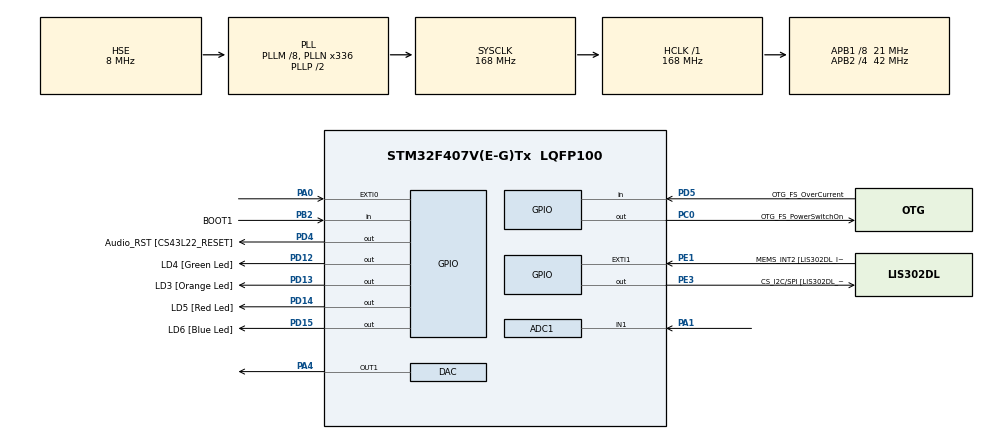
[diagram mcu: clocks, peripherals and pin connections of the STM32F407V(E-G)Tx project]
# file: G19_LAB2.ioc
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ADC1.Channel-0\#ChannelRegularConversion=ADC_CHANNEL_1
ADC1.NbrOfConversionFlag=1
ADC1.Rank-0\#ChannelRegularConversion=1
ADC1.Resolution=ADC_RESOLUTION_8B
ADC1.SamplingTime-0\#ChannelRegularConversion=ADC_SAMPLETIME_3CYCLES
ADC1.master=1
Mcu.Family=STM32F4
Mcu.Name=STM32F407V(E-G)Tx
Mcu.Package=LQFP100
NVIC.ADC_IRQn=true\:0\:0\:false\:false\:true
NVIC.EXTI0_IRQn=true\:0\:0\:false\:false\:true
NVIC.PriorityGroup=NVIC_PRIORITYGROUP_0
PA0-WKUP.Signal=GPXTI0
PA1.Signal=ADCx_IN1
PA10.GPIO_Label=OTG_FS_ID
PA10.GPIO_Mode=GPIO_MODE_AF_PP
PA10.GPIO_PuPd=GPIO_NOPULL
PA10.GPIO_Speed=GPIO_SPEED_FREQ_LOW
PA10.Signal=USB_OTG_FS_ID
PA11.GPIO_Label=OTG_FS_DM
PA11.GPIO_Mode=GPIO_MODE_AF_PP
PA11.GPIO_PuPd=GPIO_NOPULL
PA11.GPIO_Speed=GPIO_SPEED_FREQ_LOW
PA11.Signal=USB_OTG_FS_DM
PA12.GPIO_Label=OTG_FS_DP
PA12.GPIO_Mode=GPIO_MODE_AF_PP
PA12.GPIO_PuPd=GPIO_NOPULL
PA12.GPIO_Speed=GPIO_SPEED_FREQ_LOW
PA12.Signal=USB_OTG_FS_DP
PA13.GPIO_Label=SWDIO
PA13.Signal=SYS_JTMS-SWDIO
PA14.GPIO_Label=SWCLK
PA14.Signal=SYS_JTCK-SWCLK
PA4.Signal=COMP_DAC1_group
PA5.GPIO_Label=SPI1_SCK [LIS302DL_SCL/SPC]
PA5.GPIO_Mode=GPIO_MODE_AF_PP
PA5.GPIO_PuPd=GPIO_NOPULL
PA5.GPIO_Speed=GPIO_SPEED_FREQ_LOW
PA5.Signal=SPI1_SCK
PA6.GPIO_Label=SPI1_MISO [LIS302DL_SDO]
PA6.GPIO_Mode=GPIO_MODE_AF_PP
PA6.GPIO_PuPd=GPIO_NOPULL
PA6.GPIO_Speed=GPIO_SPEED_FREQ_LOW
PA6.Signal=SPI1_MISO
PA7.GPIO_Label=SPI1_MOSI [LIS302DL_SDA/SDI/SDO]
PA7.GPIO_Mode=GPIO_MODE_AF_PP
PA7.GPIO_PuPd=GPIO_NOPULL
PA7.GPIO_Speed=GPIO_SPEED_FREQ_LOW
PA7.Signal=SPI1_MOSI
PA9.GPIO_Label=VBUS_FS
PA9.GPIO_Mode=GPIO_MODE_INPUT
PA9.GPIO_PuPd=GPIO_NOPULL
PA9.Signal=USB_OTG_FS_VBUS
PB10.GPIO_Label=CLK_IN [MP45DT02_CLK]
PB10.GPIO_Mode=GPIO_MODE_AF_PP
PB10.GPIO_PuPd=GPIO_NOPULL
PB10.GPIO_Speed=GPIO_SPEED_FREQ_LOW
PB10.Signal=I2S2_CK
PB2.GPIO_Label=BOOT1
PB2.GPIO_Mode=GPIO_MODE_INPUT
PB2.GPIO_PuPd=GPIO_NOPULL
PB2.Signal=GPIO_Input
PB3.GPIO_Label=SWO
PB3.Signal=SYS_JTDO-SWO
PB6.GPIO_Label=Audio_SCL [CS43L22_SCL]
PB6.GPIO_Mode=GPIO_MODE_AF_OD
PB6.GPIO_PuPd=GPIO_NOPULL
PB6.GPIO_Speed=GPIO_SPEED_FREQ_LOW
PB6.Signal=I2C1_SCL
PB9.GPIO_Label=Audio_SDA [CS43L22_SDA]
PB9.GPIO_Mode=GPIO_MODE_AF_OD
PB9.GPIO_PuPd=GPIO_NOPULL
PB9.GPIO_Speed=GPIO_SPEED_FREQ_LOW
PB9.Signal=I2C1_SDA
PC0.GPIO_Label=OTG_FS_PowerSwitchOn
PC0.GPIO_PuPd=GPIO_NOPULL
PC0.GPIO_Speed=GPIO_SPEED_FREQ_LOW
PC0.PinState=GPIO_PIN_SET
PC0.Signal=GPIO_Output
PC10.GPIO_Label=I2S3_SCK [CS43L22_SCLK]
PC10.GPIO_Mode=GPIO_MODE_AF_PP
PC10.GPIO_PuPd=GPIO_NOPULL
PC10.GPIO_Speed=GPIO_SPEED_FREQ_LOW
PC10.Signal=I2S3_CK
PC12.GPIO_Label=I2S3_SD [CS43L22_SDIN]
PC12.GPIO_Mode=GPIO_MODE_AF_PP
PC12.GPIO_PuPd=GPIO_NOPULL
PC12.GPIO_Speed=GPIO_SPEED_FREQ_LOW
PC12.Signal=I2S3_SD
PC14-OSC32_IN.GPIO_Label=PC14-OSC32_IN
PC14-OSC32_IN.Signal=RCC_OSC32_IN
PC15-OSC32_OUT.GPIO_Label=PC15-OSC32_OUT
PC15-OSC32_OUT.Signal=RCC_OSC32_OUT
PC3.GPIO_Label=PDM_OUT [MP45DT02_DOUT]
PC3.GPIO_Mode=GPIO_MODE_AF_PP
PC3.GPIO_PuPd=GPIO_NOPULL
PC3.GPIO_Speed=GPIO_SPEED_FREQ_LOW
PC3.Signal=I2S2_SD
PC7.GPIO_Label=I2S3_MCK [CS43L22_MCLK]
PC7.GPIO_Mode=GPIO_MODE_AF_PP
PC7.GPIO_PuPd=GPIO_NOPULL
PC7.GPIO_Speed=GPIO_SPEED_FREQ_LOW
PC7.Signal=I2S3_MCK
PD12.GPIO_Label=LD4 [Green Led]
PD12.GPIO_PuPd=GPIO_NOPULL
PD12.GPIO_Speed=GPIO_SPEED_FREQ_LOW
PD12.Signal=GPIO_Output
PD13.GPIO_Label=LD3 [Orange Led]
PD13.GPIO_PuPd=GPIO_NOPULL
PD13.GPIO_Speed=GPIO_SPEED_FREQ_LOW
PD13.Signal=GPIO_Output
PD14.GPIO_Label=LD5 [Red Led]
PD14.GPIO_PuPd=GPIO_NOPULL
PD14.GPIO_Speed=GPIO_SPEED_FREQ_LOW
PD14.Signal=GPIO_Output
PD15.GPIO_Label=LD6 [Blue Led]
PD15.GPIO_PuPd=GPIO_NOPULL
PD15.GPIO_Speed=GPIO_SPEED_FREQ_LOW
PD15.Signal=GPIO_Output
PD4.GPIO_Label=Audio_RST [CS43L22_RESET]
PD4.GPIO_PuPd=GPIO_NOPULL
PD4.GPIO_Speed=GPIO_SPEED_FREQ_LOW
PD4.Signal=GPIO_Output
PD5.GPIO_Label=OTG_FS_OverCurrent
PD5.GPIO_Mode=GPIO_MODE_INPUT
PD5.GPIO_PuPd=GPIO_NOPULL
PD5.Signal=GPIO_Input
PE1.GPIO_Label=MEMS_INT2 [LIS302DL_INT2]
PE1.GPIO_ModeDefaultEXTI=GPIO_MODE_EVT_RISING
PE1.GPIO_PuPd=GPIO_NOPULL
PE1.Signal=GPXTI1
PE3.GPIO_Label=CS_I2C/SPI [LIS302DL_CS_I2C/SPI]
PE3.GPIO_PuPd=GPIO_NOPULL
PE3.GPIO_Speed=GPIO_SPEED_FREQ_LOW
PE3.Signal=GPIO_Output
PH0-OSC_IN.GPIO_Label=PH0-OSC_IN
PH0-OSC_IN.Mode=HSE-External-Oscillator
PH0-OSC_IN.Signal=RCC_OSC_IN
PH1-OSC_OUT.GPIO_Label=PH1-OSC_OUT
PH1-OSC_OUT.Mode=HSE-External-Oscillator
PH1-OSC_OUT.Signal=RCC_OSC_OUT
ProjectManager.HeapSize=0x200
ProjectManager.StackSize=0x400
ProjectManager.TargetToolchain=MDK-ARM V5
RCC.48MHZClocksFreq_Value=48000000
RCC.AHBFreq_Value=168000000
RCC.APB1CLKDivider=RCC_HCLK_DIV8
RCC.APB1Freq_Value=21000000
RCC.APB1TimFreq_Value=42000000
RCC.APB2CLKDivider=RCC_HCLK_DIV4
RCC.APB2Freq_Value=42000000
RCC.APB2TimFreq_Value=84000000
RCC.CortexFreq_Value=168000000
RCC.HCLKFreq_Value=168000000
RCC.HSE_VALUE=8000000
RCC.HSI_VALUE=16000000
RCC.LSE_VALUE=32768
RCC.PLLM=8
RCC.PLLN=336
RCC.PLLQ=7
RCC.PLLSourceVirtual=RCC_PLLSOURCE_HSE
RCC.SYSCLKFreq_VALUE=168000000
RCC.SYSCLKSource=RCC_SYSCLKSOURCE_PLLCLK
RCC.VCOOutputFreq_Value=336000000
SH.ADCx_IN1.0=ADC1_IN1,IN1
SH.COMP_DAC1_group.0=DAC_OUT1,DAC_OUT1
board=STM32F4DISCOVERY

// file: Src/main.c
/**
 ******************************************************************************
 * @file    	main.c
 * @brief       Main program body
 ******************************************************************************
 ** This notice applies to any and all portions of this file
 * that are not between comment pairs USER CODE BEGIN and
 * USER CODE END. Other portions of this file, whether
 * inserted by the user or by software development tools
 * are owned by their respective copyright owners.
 *
 * COPYRIGHT(c) 2018 STMicroelectronics
 *
 * Redistribution and use in source and binary forms, with or without modification,
 * are permitted provided that the following conditions are met:
 *   1. Redistributions of source code must retain the above copyright notice,
 *      this list of conditions and the following disclaimer.
 *   2. Redistributions in binary form must reproduce the above copyright notice,
 *      this list of conditions and the following disclaimer in the documentation
 *      and/or other materials provided with the distribution.
 *   3. Neither the name of STMicroelectronics nor the names of its contributors
 *      may be used to endorse or promote products derived from this software
 *      without specific prior written permission.
 *
 * THIS SOFTWARE IS PROVIDED BY THE COPYRIGHT HOLDERS AND CONTRIBUTORS "AS IS"
 * AND ANY EXPRESS OR IMPLIED WARRANTIES, INCLUDING, BUT NOT LIMITED TO, THE
 * IMPLIED WARRANTIES OF MERCHANTABILITY AND FITNESS FOR A PARTICULAR PURPOSE ARE
 * DISCLAIMED. IN NO EVENT SHALL THE COPYRIGHT HOLDER OR CONTRIBUTORS BE LIABLE
 * FOR ANY DIRECT, INDIRECT, INCIDENTAL, SPECIAL, EXEMPLARY, OR CONSEQUENTIAL
 * DAMAGES (INCLUDING, BUT NOT LIMITED TO, PROCUREMENT OF SUBSTITUTE GOODS OR
 * SERVICES; LOSS OF USE, DATA, OR PROFITS; OR BUSINESS INTERRUPTION) HOWEVER
 * CAUSED AND ON ANY THEORY OF LIABILITY, WHETHER IN CONTRACT, STRICT LIABILITY,
 * OR TORT (INCLUDING NEGLIGENCE OR OTHERWISE) ARISING IN ANY WAY OUT OF THE USE
 * OF THIS SOFTWARE, EVEN IF ADVISED OF THE POSSIBILITY OF SUCH DAMAGE.
 *
 ******************************************************************************
 */
#include "main.h"
#include "voltmeter.h"
#include "stm32f4xx_hal.h"

/* @brief Frequency in Hz of SysTick interrupts*/
#define SYSTICK_FREQUENCY 200
/* @brief Resolution in bits of ADC readings*/
#define ADC_RES 8

/** @brief Handle to the analog to digital converter interface*/
ADC_HandleTypeDef hadc1;
/** @brief Handle to the digital to analog converter interface*/
DAC_HandleTypeDef hdac;

void SystemClock_Config(void);
static void MX_GPIO_Init(void);
static void MX_ADC1_Init(void);
static void MX_DAC_Init(void);

/** @brief Stores latest ADC reading (digital) */
int adc_val;
/** @brief Stores latest digital value sent to the DAC */
int dac_val;
/** @brief Stores the latest values for each display mode (RMS, min, max) */
float results[3];

/** @brief Flag to change display mode, handled in EXTI0_IRQHandler() and SysTick_Handler() */
int change_mode = 0;

/** @brief Dictates which value from results[] to display */
int display_mode = RMS_MODE;

/** @brief Keeps track of SysTick interrupts for use as a software counter */
int counter = 0;

/**
 * @brief Callback function invoked when ADC has finished converting a reading
 * @param hadc Handle to the ADC unit that has finished converting a value
 * @retval None
 */
void HAL_ADC_ConvCpltCallback(ADC_HandleTypeDef* hadc) {
	adc_val = HAL_ADC_GetValue(hadc);
	float filtered_val;
	FIR_C(adc_val, &filtered_val);
	float voltage_reading = 3.3 * filtered_val / ((1 << ADC_RES) - 1.0);
	plot_point(voltage_reading, results);
}

/**
 * @brief Turns on appropriate display segments
 * @param code Byte corresponding to the segments to turn on
 * @retval None
 */
void display_num(char code) {
	if(code & SEG7_A) HAL_GPIO_WritePin(LED_A, GPIO_PIN_SET);
	else HAL_GPIO_WritePin(LED_A, GPIO_PIN_RESET);
	if(code & SEG7_B) HAL_GPIO_WritePin(LED_B, GPIO_PIN_SET);
	else HAL_GPIO_WritePin(LED_B, GPIO_PIN_RESET);
	if(code & SEG7_C) HAL_GPIO_WritePin(LED_C, GPIO_PIN_SET);
	else HAL_GPIO_WritePin(LED_C, GPIO_PIN_RESET);
	if(code & SEG7_D) HAL_GPIO_WritePin(LED_D, GPIO_PIN_SET);
	else HAL_GPIO_WritePin(LED_D, GPIO_PIN_RESET);
	if(code & SEG7_E) HAL_GPIO_WritePin(LED_E, GPIO_PIN_SET);
	else HAL_GPIO_WritePin(LED_E, GPIO_PIN_RESET);
	if(code & SEG7_F) HAL_GPIO_WritePin(LED_F, GPIO_PIN_SET);
	else HAL_GPIO_WritePin(LED_F, GPIO_PIN_RESET);
	if(code & SEG7_G) HAL_GPIO_WritePin(LED_G, GPIO_PIN_SET);
	else HAL_GPIO_WritePin(LED_G, GPIO_PIN_RESET);
	if(code & SEG7_DP) HAL_GPIO_WritePin(LED_DP, GPIO_PIN_SET);
	else HAL_GPIO_WritePin(LED_DP, GPIO_PIN_RESET);
}

int main(void)
{
	HAL_Init();
	SystemClock_Config();

	//Initialize all requisite pins and modules
	MX_GPIO_Init();
	MX_ADC1_Init();
	MX_DAC_Init();

	//Set dummy DAC value for testing
	dac_val = 0x30;
	HAL_DAC_Start(&hdac, DAC_CHANNEL_1);
	HAL_DAC_SetValue(&hdac, DAC_CHANNEL_1, DAC_ALIGN_8B_R, dac_val);

	//Initialize adc_val before the while loop
	HAL_ADC_Start_IT(&hadc1);
	adc_val = HAL_ADC_GetValue(&hadc1);

	//Initialize LEDs to represent RMS mode
	HAL_GPIO_WritePin(GPIOD, RMS_PIN, GPIO_PIN_SET);

	while (1)
	{
		//Multiplex 7-segment displays and display corresponding number
		if(counter % 3 == 0) {
			display_num(get_display_leds((int)(results[display_mode] * 100) % 100));
			HAL_GPIO_WritePin(LED_DP, GPIO_PIN_RESET);
			HAL_GPIO_WritePin(DIG_SEL_ONES, GPIO_PIN_SET);
			HAL_GPIO_WritePin(DIG_SEL_TENTHS, GPIO_PIN_RESET);
			HAL_GPIO_WritePin(DIG_SEL_HUNDREDTHS, GPIO_PIN_RESET);
		} else if(counter % 3 == 1) {
			display_num(get_display_leds((int)(results[display_mode] * 10) % 10));
			HAL_GPIO_WritePin(LED_DP, GPIO_PIN_RESET);
			HAL_GPIO_WritePin(DIG_SEL_ONES, GPIO_PIN_RESET);
			HAL_GPIO_WritePin(DIG_SEL_TENTHS, GPIO_PIN_SET);
			HAL_GPIO_WritePin(DIG_SEL_HUNDREDTHS, GPIO_PIN_RESET);
		} else {
			display_num(get_display_leds((int)results[display_mode]));
			HAL_GPIO_WritePin(LED_DP, GPIO_PIN_SET);
			HAL_GPIO_WritePin(DIG_SEL_ONES, GPIO_PIN_RESET);
			HAL_GPIO_WritePin(DIG_SEL_TENTHS, GPIO_PIN_RESET);
			HAL_GPIO_WritePin(DIG_SEL_HUNDREDTHS, GPIO_PIN_SET);
		}

		//Refresh mode LEDs at 100Hz
		if(counter % 2 == 0) {
			HAL_GPIO_WritePin(GPIOD, RMS_PIN, GPIO_PIN_RESET);
			HAL_GPIO_WritePin(GPIOD, MAX_PIN, GPIO_PIN_RESET);
			HAL_GPIO_WritePin(GPIOD, MIN_PIN, GPIO_PIN_RESET);
			switch(display_mode) {
				case RMS_MODE:
					HAL_GPIO_WritePin(GPIOD, RMS_PIN, GPIO_PIN_SET);
					break;
				case MIN_MODE:
					HAL_GPIO_WritePin(GPIOD, MIN_PIN, GPIO_PIN_SET);
					break;
				case MAX_MODE:
					HAL_GPIO_WritePin(GPIOD, MAX_PIN, GPIO_PIN_SET);
					break;
				default:
					break;
			}
		}
	}
}

/** @brief System Clock Configuration
*/
void SystemClock_Config(void)
{

	RCC_OscInitTypeDef RCC_OscInitStruct;
	RCC_ClkInitTypeDef RCC_ClkInitStruct;

	/**Configure the main internal regulator output voltage
	*/
	__HAL_RCC_PWR_CLK_ENABLE();

	__HAL_PWR_VOLTAGESCALING_CONFIG(PWR_REGULATOR_VOLTAGE_SCALE1);

	/**Initializes the CPU, AHB and APB busses clocks
	*/
	RCC_OscInitStruct.OscillatorType = RCC_OSCILLATORTYPE_HSE;
	RCC_OscInitStruct.HSEState = RCC_HSE_ON;
	RCC_OscInitStruct.PLL.PLLState = RCC_PLL_ON;
	RCC_OscInitStruct.PLL.PLLSource = RCC_PLLSOURCE_HSE;
	RCC_OscInitStruct.PLL.PLLM = 8;
	RCC_OscInitStruct.PLL.PLLN = 336;
	RCC_OscInitStruct.PLL.PLLP = RCC_PLLP_DIV2;
	RCC_OscInitStruct.PLL.PLLQ = 7;
	if (HAL_RCC_OscConfig(&RCC_OscInitStruct) != HAL_OK)
	{
		_Error_Handler(__FILE__, __LINE__);
	}

	/**Initializes the CPU, AHB and APB busses clocks
	*/
	RCC_ClkInitStruct.ClockType = RCC_CLOCKTYPE_HCLK|RCC_CLOCKTYPE_SYSCLK
		|RCC_CLOCKTYPE_PCLK1|RCC_CLOCKTYPE_PCLK2;
	RCC_ClkInitStruct.SYSCLKSource = RCC_SYSCLKSOURCE_PLLCLK;
	RCC_ClkInitStruct.AHBCLKDivider = RCC_SYSCLK_DIV1;
	RCC_ClkInitStruct.APB1CLKDivider = RCC_HCLK_DIV8;
	RCC_ClkInitStruct.APB2CLKDivider = RCC_HCLK_DIV4;

	if (HAL_RCC_ClockConfig(&RCC_ClkInitStruct, FLASH_LATENCY_5) != HAL_OK)
	{
		_Error_Handler(__FILE__, __LINE__);
	}

	/**Configure the Systick interrupt time
	*/
	HAL_SYSTICK_Config(HAL_RCC_GetHCLKFreq()/SYSTICK_FREQUENCY);

	/**Configure the Systick
	*/
	HAL_SYSTICK_CLKSourceConfig(SYSTICK_CLKSOURCE_HCLK);

	/* SysTick_IRQn interrupt configuration */
	HAL_NVIC_SetPriority(SysTick_IRQn, 0, 0);
}

/** @brief ADC1 init function */
static void MX_ADC1_Init(void)
{

	ADC_ChannelConfTypeDef sConfig;

	/**Configure the global features of the ADC (Clock, Resolution, Data Alignment and number of conversion)
	*/
	hadc1.Instance = ADC1;
	hadc1.Init.ClockPrescaler = ADC_CLOCK_SYNC_PCLK_DIV2;
	hadc1.Init.Resolution = ADC_RESOLUTION_8B;
	hadc1.Init.ScanConvMode = DISABLE;
	hadc1.Init.ContinuousConvMode = DISABLE;
	hadc1.Init.DiscontinuousConvMode = DISABLE;
	hadc1.Init.ExternalTrigConvEdge = ADC_EXTERNALTRIGCONVEDGE_RISING;
	hadc1.Init.ExternalTrigConv = ADC_SOFTWARE_START;
	hadc1.Init.DataAlign = ADC_DATAALIGN_RIGHT;
	hadc1.Init.NbrOfConversion = 1;
	hadc1.Init.DMAContinuousRequests = DISABLE;
	hadc1.Init.EOCSelection = ADC_EOC_SINGLE_CONV;
	if (HAL_ADC_Init(&hadc1) != HAL_OK)
	{
		_Error_Handler(__FILE__, __LINE__);
	}

	/**Configure for the selected ADC regular channel its corresponding rank in the sequencer and its sample time.
	*/
	sConfig.Channel = ADC_CHANNEL_1;
	sConfig.Rank = 1;
	sConfig.SamplingTime = ADC_SAMPLETIME_3CYCLES;
	if (HAL_ADC_ConfigChannel(&hadc1, &sConfig) != HAL_OK)
	{
		_Error_Handler(__FILE__, __LINE__);
	}

}

/** @brief DAC init function */
static void MX_DAC_Init(void)
{

	DAC_ChannelConfTypeDef sConfig;

	/**DAC Initialization
	*/
	hdac.Instance = DAC;
	if (HAL_DAC_Init(&hdac) != HAL_OK)
	{
		_Error_Handler(__FILE__, __LINE__);
	}

	/**DAC channel OUT1 config
	*/
	sConfig.DAC_Trigger = DAC_TRIGGER_NONE;
	sConfig.DAC_OutputBuffer = DAC_OUTPUTBUFFER_ENABLE;
	if (HAL_DAC_ConfigChannel(&hdac, &sConfig, DAC_CHANNEL_1) != HAL_OK)
	{
		_Error_Handler(__FILE__, __LINE__);
	}

}

/** Configure pins as
 * Analog
 * Input
 * Output
 * EVENT_OUT
 * EXTI
 PC3   ------> I2S2_SD
 PA5   ------> SPI1_SCK
 PA6   ------> SPI1_MISO
 PA7   ------> SPI1_MOSI
 PB10   ------> I2S2_CK
 PC7   ------> I2S3_MCK
 PA9   ------> USB_OTG_FS_VBUS
 PA10   ------> USB_OTG_FS_ID
 PA11   ------> USB_OTG_FS_DM
 PA12   ------> USB_OTG_FS_DP
 PC10   ------> I2S3_CK
 PC12   ------> I2S3_SD
 PB6   ------> I2C1_SCL
 PB9   ------> I2C1_SDA
 */
static void MX_GPIO_Init(void)
{

	GPIO_InitTypeDef GPIO_InitStruct;

	/* GPIO Ports Clock Enable */
	__HAL_RCC_GPIOE_CLK_ENABLE();
	__HAL_RCC_GPIOC_CLK_ENABLE();
	__HAL_RCC_GPIOH_CLK_ENABLE();
	__HAL_RCC_GPIOA_CLK_ENABLE();
	__HAL_RCC_GPIOB_CLK_ENABLE();
	__HAL_RCC_GPIOD_CLK_ENABLE();

	/*Configure GPIO pin Output Level */
	HAL_GPIO_WritePin(CS_I2C_SPI_GPIO_Port, CS_I2C_SPI_Pin, GPIO_PIN_RESET);

	/*Configure GPIO pin Output Level */
	HAL_GPIO_WritePin(OTG_FS_PowerSwitchOn_GPIO_Port, OTG_FS_PowerSwitchOn_Pin, GPIO_PIN_SET);

	/*Configure GPIO pin Output Level */
	HAL_GPIO_WritePin(GPIOD, LD4_Pin|LD3_Pin|LD5_Pin|LD6_Pin
			|Audio_RST_Pin, GPIO_PIN_RESET);

	HAL_GPIO_WritePin(GPIOE, GPIO_PIN_7|GPIO_PIN_11|GPIO_PIN_10|GPIO_PIN_14|GPIO_PIN_15, GPIO_PIN_RESET);
	HAL_GPIO_WritePin(GPIOB, GPIO_PIN_12|GPIO_PIN_13, GPIO_PIN_RESET);
	HAL_GPIO_WritePin(GPIOD, GPIO_PIN_8, GPIO_PIN_RESET);

	/*Configure GPIO pin : CS_I2C_SPI_Pin */
	GPIO_InitStruct.Pin = CS_I2C_SPI_Pin;
	GPIO_InitStruct.Mode = GPIO_MODE_OUTPUT_PP;
	GPIO_InitStruct.Pull = GPIO_NOPULL;
	GPIO_InitStruct.Speed = GPIO_SPEED_FREQ_LOW;
	HAL_GPIO_Init(CS_I2C_SPI_GPIO_Port, &GPIO_InitStruct);

	/*Configure GPIO pin : OTG_FS_PowerSwitchOn_Pin */
	GPIO_InitStruct.Pin = OTG_FS_PowerSwitchOn_Pin;
	GPIO_InitStruct.Mode = GPIO_MODE_OUTPUT_PP;
	GPIO_InitStruct.Pull = GPIO_NOPULL;
	GPIO_InitStruct.Speed = GPIO_SPEED_FREQ_LOW;
	HAL_GPIO_Init(OTG_FS_PowerSwitchOn_GPIO_Port, &GPIO_InitStruct);

	/*Configure GPIO pin : PDM_OUT_Pin */
	GPIO_InitStruct.Pin = PDM_OUT_Pin;
	GPIO_InitStruct.Mode = GPIO_MODE_AF_PP;
	GPIO_InitStruct.Pull = GPIO_NOPULL;
	GPIO_InitStruct.Speed = GPIO_SPEED_FREQ_LOW;
	GPIO_InitStruct.Alternate = GPIO_AF5_SPI2;
	HAL_GPIO_Init(PDM_OUT_GPIO_Port, &GPIO_InitStruct);

	/*Configure GPIO pin : PA0 */
	GPIO_InitStruct.Pin = GPIO_PIN_0;
	GPIO_InitStruct.Mode = GPIO_MODE_IT_RISING;
	GPIO_InitStruct.Pull = GPIO_NOPULL;
	HAL_GPIO_Init(GPIOA, &GPIO_InitStruct);

	/*Configure GPIO pins : SPI1_SCK_Pin SPI1_MISO_Pin SPI1_MOSI_Pin */
	GPIO_InitStruct.Pin = SPI1_SCK_Pin|SPI1_MISO_Pin|SPI1_MOSI_Pin;
	GPIO_InitStruct.Mode = GPIO_MODE_AF_PP;
	GPIO_InitStruct.Pull = GPIO_NOPULL;
	GPIO_InitStruct.Speed = GPIO_SPEED_FREQ_LOW;
	GPIO_InitStruct.Alternate = GPIO_AF5_SPI1;
	HAL_GPIO_Init(GPIOA, &GPIO_InitStruct);

	/*Configure GPIO pin : BOOT1_Pin */
	GPIO_InitStruct.Pin = BOOT1_Pin;
	GPIO_InitStruct.Mode = GPIO_MODE_INPUT;
	GPIO_InitStruct.Pull = GPIO_NOPULL;
	HAL_GPIO_Init(BOOT1_GPIO_Port, &GPIO_InitStruct);

	/*Configure GPIO pin : CLK_IN_Pin */
	GPIO_InitStruct.Pin = CLK_IN_Pin;
	GPIO_InitStruct.Mode = GPIO_MODE_AF_PP;
	GPIO_InitStruct.Pull = GPIO_NOPULL;
	GPIO_InitStruct.Speed = GPIO_SPEED_FREQ_LOW;
	GPIO_InitStruct.Alternate = GPIO_AF5_SPI2;
	HAL_GPIO_Init(CLK_IN_GPIO_Port, &GPIO_InitStruct);

	/*Configure GPIO pins : LD4_Pin LD3_Pin LD5_Pin LD6_Pin
	  Audio_RST_Pin */
	GPIO_InitStruct.Pin = LD4_Pin|LD3_Pin|LD5_Pin|LD6_Pin
		|Audio_RST_Pin;
	GPIO_InitStruct.Mode = GPIO_MODE_OUTPUT_PP;
	GPIO_InitStruct.Pull = GPIO_NOPULL;
	GPIO_InitStruct.Speed = GPIO_SPEED_FREQ_LOW;
	HAL_GPIO_Init(GPIOD, &GPIO_InitStruct);

	/*Configure 7 segment pins*/
	GPIO_InitStruct.Pin = GPIO_PIN_7|GPIO_PIN_11|GPIO_PIN_10|GPIO_PIN_14|GPIO_PIN_15;
	GPIO_InitStruct.Mode = GPIO_MODE_OUTPUT_PP;
	GPIO_InitStruct.Pull = GPIO_NOPULL;
	GPIO_InitStruct.Speed = GPIO_SPEED_FREQ_LOW;
	HAL_GPIO_Init(GPIOE, &GPIO_InitStruct);
	GPIO_InitStruct.Pin = GPIO_PIN_12|GPIO_PIN_13;
	GPIO_InitStruct.Mode = GPIO_MODE_OUTPUT_PP;
	GPIO_InitStruct.Pull = GPIO_NOPULL;
	GPIO_InitStruct.Speed = GPIO_SPEED_FREQ_LOW;
	HAL_GPIO_Init(GPIOB, &GPIO_InitStruct);
	GPIO_InitStruct.Pin = GPIO_PIN_8;
	GPIO_InitStruct.Mode = GPIO_MODE_OUTPUT_PP;
	GPIO_InitStruct.Pull = GPIO_NOPULL;
	GPIO_InitStruct.Speed = GPIO_SPEED_FREQ_LOW;
	HAL_GPIO_Init(GPIOD, &GPIO_InitStruct);

	/*Configure digit selector pins*/
	GPIO_InitStruct.Pin = GPIO_PIN_7|GPIO_PIN_3|GPIO_PIN_0;
	GPIO_InitStruct.Mode = GPIO_MODE_OUTPUT_PP;
	GPIO_InitStruct.Pull = GPIO_NOPULL;
	GPIO_InitStruct.Speed = GPIO_SPEED_FREQ_LOW;
	HAL_GPIO_Init(GPIOD, &GPIO_InitStruct);

	/*Configure 7 segment display leds*/
	GPIO_InitStruct.Pin = GPIO_PIN_2|GPIO_PIN_4|GPIO_PIN_6|GPIO_PIN_8;
	GPIO_InitStruct.Mode = GPIO_MODE_OUTPUT_PP;
	GPIO_InitStruct.Pull = GPIO_NOPULL;
	GPIO_InitStruct.Speed = GPIO_SPEED_FREQ_LOW;
	HAL_GPIO_Init(GPIOD, &GPIO_InitStruct);
	GPIO_InitStruct.Pin = GPIO_PIN_2|GPIO_PIN_4|GPIO_PIN_6|GPIO_PIN_8;
	GPIO_InitStruct.Mode = GPIO_MODE_OUTPUT_PP;
	GPIO_InitStruct.Pull = GPIO_NOPULL;
	GPIO_InitStruct.Speed = GPIO_SPEED_FREQ_LOW;
	HAL_GPIO_Init(GPIOE, &GPIO_InitStruct);

	/*Configure GPIO pins : I2S3_MCK_Pin I2S3_SCK_Pin I2S3_SD_Pin */
	GPIO_InitStruct.Pin = I2S3_MCK_Pin|I2S3_SCK_Pin|I2S3_SD_Pin;
	GPIO_InitStruct.Mode = GPIO_MODE_AF_PP;
	GPIO_InitStruct.Pull = GPIO_NOPULL;
	GPIO_InitStruct.Speed = GPIO_SPEED_FREQ_LOW;
	GPIO_InitStruct.Alternate = GPIO_AF6_SPI3;
	HAL_GPIO_Init(GPIOC, &GPIO_InitStruct);

	/*Configure GPIO pin : VBUS_FS_Pin */
	GPIO_InitStruct.Pin = VBUS_FS_Pin;
	GPIO_InitStruct.Mode = GPIO_MODE_INPUT;
	GPIO_InitStruct.Pull = GPIO_NOPULL;
	HAL_GPIO_Init(VBUS_FS_GPIO_Port, &GPIO_InitStruct);

	/*Configure GPIO pins : OTG_FS_ID_Pin OTG_FS_DM_Pin OTG_FS_DP_Pin */
	GPIO_InitStruct.Pin = OTG_FS_ID_Pin|OTG_FS_DM_Pin|OTG_FS_DP_Pin;
	GPIO_InitStruct.Mode = GPIO_MODE_AF_PP;
	GPIO_InitStruct.Pull = GPIO_NOPULL;
	GPIO_InitStruct.Speed = GPIO_SPEED_FREQ_LOW;
	GPIO_InitStruct.Alternate = GPIO_AF10_OTG_FS;
	HAL_GPIO_Init(GPIOA, &GPIO_InitStruct);

	/*Configure GPIO pin : OTG_FS_OverCurrent_Pin */
	GPIO_InitStruct.Pin = OTG_FS_OverCurrent_Pin;
	GPIO_InitStruct.Mode = GPIO_MODE_INPUT;
	GPIO_InitStruct.Pull = GPIO_NOPULL;
	HAL_GPIO_Init(OTG_FS_OverCurrent_GPIO_Port, &GPIO_InitStruct);

	/*Configure GPIO pins : Audio_SCL_Pin Audio_SDA_Pin */
	GPIO_InitStruct.Pin = Audio_SCL_Pin|Audio_SDA_Pin;
	GPIO_InitStruct.Mode = GPIO_MODE_AF_OD;
	GPIO_InitStruct.Pull = GPIO_PULLUP;
	GPIO_InitStruct.Speed = GPIO_SPEED_FREQ_LOW;
	GPIO_InitStruct.Alternate = GPIO_AF4_I2C1;
	HAL_GPIO_Init(GPIOB, &GPIO_InitStruct);

	/*Configure GPIO pin : MEMS_INT2_Pin */
	GPIO_InitStruct.Pin = MEMS_INT2_Pin;
	GPIO_InitStruct.Mode = GPIO_MODE_EVT_RISING;
	GPIO_InitStruct.Pull = GPIO_NOPULL;
	HAL_GPIO_Init(MEMS_INT2_GPIO_Port, &GPIO_InitStruct);

	/* EXTI interrupt init*/
	HAL_NVIC_SetPriority(EXTI0_IRQn, 0, 0);
	HAL_NVIC_EnableIRQ(EXTI0_IRQn);

}

void _Error_Handler(char * file, int line)
{
	while(1)
	{
	}
}

/************************ (C) COPYRIGHT STMicroelectronics *****END OF FILE****/
